VERSION 5.7 ;
  NOWIREEXTENSIONATPIN ON ;
  DIVIDERCHAR "/" ;
  BUSBITCHARS "[]" ;
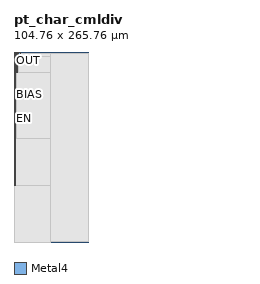
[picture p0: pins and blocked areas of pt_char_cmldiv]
MACRO pt_char_cmldiv
  CLASS BLOCK ;
  FOREIGN pt_char_cmldiv ;
  ORIGIN 10.500 -0.800 ;
  SIZE 104.760 BY 265.760 ;
  PIN EN
    ANTENNAGATEAREA 0.840000 ;
    PORT
      LAYER Metal4 ;
        RECT -9.400 79.580 -9.000 266.560 ;
    END
  END EN
  PIN OUT
    ANTENNADIFFAREA 5.280000 ;
    PORT
      LAYER Metal4 ;
        RECT -10.400 258.700 -10.000 266.560 ;
    END
  END OUT
  PIN BIAS
    ANTENNAGATEAREA 35.500000 ;
    ANTENNADIFFAREA 0.880000 ;
    PORT
      LAYER Metal4 ;
        RECT -8.400 146.480 -8.000 266.560 ;
    END
  END BIAS
  PIN VDD
    USE POWER ;
    PORT
      LAYER Metal4 ;
        RECT -4.000 260.500 -2.000 266.560 ;
    END
  END VDD
  PIN VSS
    USE GROUND ;
    PORT
      LAYER Metal4 ;
        RECT -7.000 237.740 -5.000 266.560 ;
    END
  END VSS
  OBS
      LAYER Nwell ;
        RECT 0.000 12.000 94.260 256.860 ;
      LAYER Metal1 ;
        RECT 0.185 12.110 94.075 256.675 ;
      LAYER Metal2 ;
        RECT 0.335 0.900 93.470 264.360 ;
      LAYER Metal3 ;
        RECT -10.500 0.900 93.570 264.360 ;
      LAYER Metal4 ;
        RECT -10.400 79.280 -9.700 258.400 ;
        RECT -7.700 237.440 -7.300 264.360 ;
        RECT -4.700 260.200 -4.300 264.360 ;
        RECT -1.700 260.200 41.085 264.360 ;
        RECT -4.700 237.440 41.085 260.200 ;
        RECT -7.700 146.180 41.085 237.440 ;
        RECT -8.700 79.280 41.085 146.180 ;
        RECT -10.400 0.800 41.085 79.280 ;
  END
END pt_char_cmldiv
END LIBRARY

